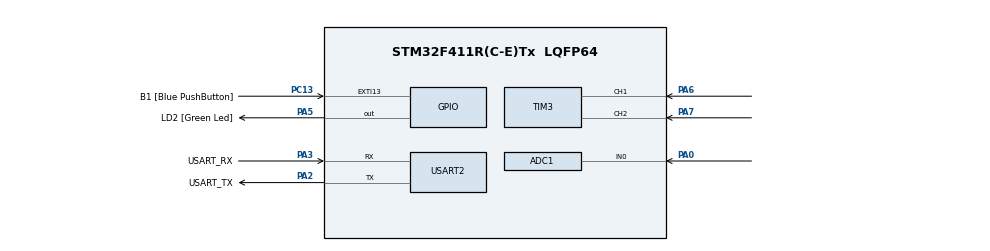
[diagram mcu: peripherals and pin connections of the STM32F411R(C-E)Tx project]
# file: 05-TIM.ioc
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Mcu.Family=STM32F4
RCC.CortexFreq_Value=100000000
Dma.TIM3_CH2.1.Mode=DMA_NORMAL
PA14.GPIO_Label=TCK
Dma.TIM3_CH1/TRIG.0.MemDataAlignment=DMA_MDATAALIGN_HALFWORD
Dma.TIM3_CH2.1.MemDataAlignment=DMA_MDATAALIGN_HALFWORD
NVIC.DMA1_Stream4_IRQn=true\:0\:0\:false\:false\:true\:false\:true
RCC.SYSCLKSource=RCC_SYSCLKSOURCE_PLLCLK
ProjectManager.StackSize=0x400
Dma.TIM3_CH2.1.PeriphInc=DMA_PINC_DISABLE
PH0\ -\ OSC_IN.Signal=RCC_OSC_IN
Dma.TIM3_CH2.1.Priority=DMA_PRIORITY_LOW
RCC.HCLKFreq_Value=100000000
RCC.APB2TimFreq_Value=100000000
Dma.TIM3_CH2.1.PeriphDataAlignment=DMA_PDATAALIGN_HALFWORD
RCC.AHBFreq_Value=100000000
ADC1.Channel-0\#ChannelRegularConversion=ADC_CHANNEL_0
RCC.HSE_VALUE=8000000
TIM3.Channel-Input_Capture1_from_TI1=TIM_CHANNEL_1
PC13-ANTI_TAMP.Signal=GPXTI13
PC14-OSC32_IN.Mode=LSE-External-Oscillator
Dma.TIM3_CH2.1.MemInc=DMA_MINC_ENABLE
Dma.TIM3_CH1/TRIG.0.PeriphDataAlignment=DMA_PDATAALIGN_HALFWORD
PA14.Mode=Serial_Wire
Dma.TIM3_CH1/TRIG.0.Priority=DMA_PRIORITY_LOW
SH.ADCx_IN0.0=ADC1_IN0,IN0
SH.S_TIM3_CH1.0=TIM3_CH1,Input_Capture1_from_TI1
ADC1.SamplingTime-0\#ChannelRegularConversion=ADC_SAMPLETIME_3CYCLES
RCC.FLatency-AdvancedSettings=FLASH_LATENCY_3
Mcu.Package=LQFP64
PA6.Signal=S_TIM3_CH1
USART2.VirtualMode=VM_ASYNC
PA2.GPIO_Label=USART_TX
Dma.TIM3_CH2.1.FIFOMode=DMA_FIFOMODE_DISABLE
Dma.TIM3_CH2.1.Instance=DMA1_Stream5
Dma.Request1=TIM3_CH2
RCC.APB1TimFreq_Value=100000000
Dma.Request0=TIM3_CH1/TRIG
VP_TIM3_VS_ClockSourceINT.Mode=Internal
PA3.Signal=USART2_RX
PB3.GPIO_Label=SWO
PC15-OSC32_OUT.Mode=LSE-External-Oscillator
ADC1.Rank-0\#ChannelRegularConversion=1
TIM3.Channel-Input_Capture2_from_TI2=TIM_CHANNEL_2
PC13-ANTI_TAMP.GPIO_Label=B1 [Blue PushButton]
Dma.TIM3_CH1/TRIG.0.PeriphInc=DMA_PINC_DISABLE
PH1\ -\ OSC_OUT.Mode=HSE-External-Clock-Source
Dma.TIM3_CH2.1.Direction=DMA_PERIPH_TO_MEMORY
Dma.TIM3_CH1/TRIG.0.MemInc=DMA_MINC_ENABLE
RCC.APB1CLKDivider=RCC_HCLK_DIV2
PC14-OSC32_IN.Signal=RCC_OSC32_IN
PA0-WKUP.Signal=ADCx_IN0
PA13.Signal=SYS_JTMS-SWDIO
PA3.Mode=Asynchronous
PH0\ -\ OSC_IN.Mode=HSE-External-Clock-Source
ProjectManager.TargetToolchain=STM32CubeIDE
NVIC.DMA1_Stream5_IRQn=true\:0\:0\:false\:false\:true\:false\:true
PC15-OSC32_OUT.Signal=RCC_OSC32_OUT
PA5.Signal=GPIO_Output
SH.S_TIM3_CH2.0=TIM3_CH2,Input_Capture2_from_TI2
PH1\ -\ OSC_OUT.Signal=RCC_OSC_OUT
board=NUCLEO-F411RE
RCC.VCOOutputFreq_Value=200000000
ADC1.EnableAnalogWatchDog=false
RCC.APB2Freq_Value=100000000
PA13.Mode=Serial_Wire
Mcu.Name=STM32F411R(C-E)Tx
Dma.TIM3_CH1/TRIG.0.FIFOMode=DMA_FIFOMODE_DISABLE
PA13.GPIO_Label=TMS
PA2.Signal=USART2_TX
Dma.TIM3_CH1/TRIG.0.Mode=DMA_NORMAL
RCC.48MHZClocksFreq_Value=50000000
PB3.Signal=SYS_JTDO-SWO
RCC.SYSCLKFreq_VALUE=100000000
ADC1.master=1
PA5.GPIO_Label=LD2 [Green Led]
Dma.TIM3_CH1/TRIG.0.Direction=DMA_PERIPH_TO_MEMORY
PC13-ANTI_TAMP.GPIO_ModeDefaultEXTI=GPIO_MODE_IT_FALLING
PA14.Signal=SYS_JTCK-SWCLK
ProjectManager.HeapSize=0x200
RCC.HSI_VALUE=16000000
NVIC.PriorityGroup=NVIC_PRIORITYGROUP_0
ADC1.NbrOfConversionFlag=1
Dma.TIM3_CH1/TRIG.0.Instance=DMA1_Stream4
RCC.PLLM=8
RCC.PLLN=100
PA2.Mode=Asynchronous
RCC.APB1Freq_Value=50000000
PA3.GPIO_Label=USART_RX
PA7.Signal=S_TIM3_CH2

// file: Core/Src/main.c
/* USER CODE BEGIN Header */
/**
  ******************************************************************************
  * @file           : main.c
  * @brief          : Main program body
  ******************************************************************************
  * @attention
  *
  * <h2><center>&copy; Copyright (c) 2021 STMicroelectronics.
  * All rights reserved.</center></h2>
  *
  * This software component is licensed by ST under BSD 3-Clause license,
  * the "License"; You may not use this file except in compliance with the
  * License. You may obtain a copy of the License at:
  *                        opensource.org/licenses/BSD-3-Clause
  *
  ******************************************************************************
  */
/* USER CODE END Header */
#include "main.h"

ADC_HandleTypeDef hadc1;

TIM_HandleTypeDef htim3;
DMA_HandleTypeDef hdma_tim3_ch1_trig;
DMA_HandleTypeDef hdma_tim3_ch2;

UART_HandleTypeDef huart2;

void SystemClock_Config(void);
static void MX_GPIO_Init(void);
static void MX_DMA_Init(void);
static void MX_USART2_UART_Init(void);
static void MX_TIM3_Init(void);
static void MX_ADC1_Init(void);

int main(void)
{

  /* MCU Configuration--------------------------------------------------------*/

  /* Reset of all peripherals, Initializes the Flash interface and the Systick. */
  HAL_Init();

  /* Configure the system clock */
  SystemClock_Config();

  /* Initialize all configured peripherals */
  MX_GPIO_Init();
  MX_DMA_Init();
  MX_USART2_UART_Init();
  MX_TIM3_Init();
  MX_ADC1_Init();

  /* Infinite loop */
  while (1)
  {

    /* USER CODE BEGIN 3 */
	  __HAL_DMA_GET_COUNTER(htim3->hdma);
  }
  /* USER CODE END 3 */
}

void SystemClock_Config(void)
{
  RCC_OscInitTypeDef RCC_OscInitStruct = {0};
  RCC_ClkInitTypeDef RCC_ClkInitStruct = {0};

  /** Configure the main internal regulator output voltage
  */
  __HAL_RCC_PWR_CLK_ENABLE();
  __HAL_PWR_VOLTAGESCALING_CONFIG(PWR_REGULATOR_VOLTAGE_SCALE1);
  /** Initializes the RCC Oscillators according to the specified parameters
  * in the RCC_OscInitTypeDef structure.
  */
  RCC_OscInitStruct.OscillatorType = RCC_OSCILLATORTYPE_HSI;
  RCC_OscInitStruct.HSIState = RCC_HSI_ON;
  RCC_OscInitStruct.HSICalibrationValue = RCC_HSICALIBRATION_DEFAULT;
  RCC_OscInitStruct.PLL.PLLState = RCC_PLL_ON;
  RCC_OscInitStruct.PLL.PLLSource = RCC_PLLSOURCE_HSI;
  RCC_OscInitStruct.PLL.PLLM = 16;
  RCC_OscInitStruct.PLL.PLLN = 336;
  RCC_OscInitStruct.PLL.PLLP = RCC_PLLP_DIV4;
  RCC_OscInitStruct.PLL.PLLQ = 4;
  if (HAL_RCC_OscConfig(&RCC_OscInitStruct) != HAL_OK)
  {
    Error_Handler();
  }
  /** Initializes the CPU, AHB and APB buses clocks
  */
  RCC_ClkInitStruct.ClockType = RCC_CLOCKTYPE_HCLK|RCC_CLOCKTYPE_SYSCLK
                              |RCC_CLOCKTYPE_PCLK1|RCC_CLOCKTYPE_PCLK2;
  RCC_ClkInitStruct.SYSCLKSource = RCC_SYSCLKSOURCE_PLLCLK;
  RCC_ClkInitStruct.AHBCLKDivider = RCC_SYSCLK_DIV1;
  RCC_ClkInitStruct.APB1CLKDivider = RCC_HCLK_DIV2;
  RCC_ClkInitStruct.APB2CLKDivider = RCC_HCLK_DIV1;

  if (HAL_RCC_ClockConfig(&RCC_ClkInitStruct, FLASH_LATENCY_2) != HAL_OK)
  {
    Error_Handler();
  }
}

static void MX_ADC1_Init(void)
{

  ADC_ChannelConfTypeDef sConfig = {0};

  /** Configure the global features of the ADC (Clock, Resolution, Data Alignment and number of conversion)
  */
  hadc1.Instance = ADC1;
  hadc1.Init.ClockPrescaler = ADC_CLOCK_SYNC_PCLK_DIV4;
  hadc1.Init.Resolution = ADC_RESOLUTION_12B;
  hadc1.Init.ScanConvMode = DISABLE;
  hadc1.Init.ContinuousConvMode = DISABLE;
  hadc1.Init.DiscontinuousConvMode = DISABLE;
  hadc1.Init.ExternalTrigConvEdge = ADC_EXTERNALTRIGCONVEDGE_NONE;
  hadc1.Init.ExternalTrigConv = ADC_SOFTWARE_START;
  hadc1.Init.DataAlign = ADC_DATAALIGN_RIGHT;
  hadc1.Init.NbrOfConversion = 1;
  hadc1.Init.DMAContinuousRequests = DISABLE;
  hadc1.Init.EOCSelection = ADC_EOC_SINGLE_CONV;
  if (HAL_ADC_Init(&hadc1) != HAL_OK)
  {
    Error_Handler();
  }
  /** Configure for the selected ADC regular channel its corresponding rank in the sequencer and its sample time.
  */
  sConfig.Channel = ADC_CHANNEL_0;
  sConfig.Rank = 1;
  sConfig.SamplingTime = ADC_SAMPLETIME_3CYCLES;
  if (HAL_ADC_ConfigChannel(&hadc1, &sConfig) != HAL_OK)
  {
    Error_Handler();
  }

}

static void MX_TIM3_Init(void)
{

  TIM_ClockConfigTypeDef sClockSourceConfig = {0};
  TIM_MasterConfigTypeDef sMasterConfig = {0};
  TIM_IC_InitTypeDef sConfigIC = {0};

  htim3.Instance = TIM3;
  htim3.Init.Prescaler = 0;
  htim3.Init.CounterMode = TIM_COUNTERMODE_UP;
  htim3.Init.Period = 65535;
  htim3.Init.ClockDivision = TIM_CLOCKDIVISION_DIV1;
  htim3.Init.AutoReloadPreload = TIM_AUTORELOAD_PRELOAD_DISABLE;
  if (HAL_TIM_Base_Init(&htim3) != HAL_OK)
  {
    Error_Handler();
  }
  sClockSourceConfig.ClockSource = TIM_CLOCKSOURCE_INTERNAL;
  if (HAL_TIM_ConfigClockSource(&htim3, &sClockSourceConfig) != HAL_OK)
  {
    Error_Handler();
  }
  if (HAL_TIM_IC_Init(&htim3) != HAL_OK)
  {
    Error_Handler();
  }
  sMasterConfig.MasterOutputTrigger = TIM_TRGO_RESET;
  sMasterConfig.MasterSlaveMode = TIM_MASTERSLAVEMODE_DISABLE;
  if (HAL_TIMEx_MasterConfigSynchronization(&htim3, &sMasterConfig) != HAL_OK)
  {
    Error_Handler();
  }
  sConfigIC.ICPolarity = TIM_INPUTCHANNELPOLARITY_RISING;
  sConfigIC.ICSelection = TIM_ICSELECTION_DIRECTTI;
  sConfigIC.ICPrescaler = TIM_ICPSC_DIV1;
  sConfigIC.ICFilter = 0;
  if (HAL_TIM_IC_ConfigChannel(&htim3, &sConfigIC, TIM_CHANNEL_1) != HAL_OK)
  {
    Error_Handler();
  }
  if (HAL_TIM_IC_ConfigChannel(&htim3, &sConfigIC, TIM_CHANNEL_2) != HAL_OK)
  {
    Error_Handler();
  }

}

static void MX_USART2_UART_Init(void)
{

  huart2.Instance = USART2;
  huart2.Init.BaudRate = 115200;
  huart2.Init.WordLength = UART_WORDLENGTH_8B;
  huart2.Init.StopBits = UART_STOPBITS_1;
  huart2.Init.Parity = UART_PARITY_NONE;
  huart2.Init.Mode = UART_MODE_TX_RX;
  huart2.Init.HwFlowCtl = UART_HWCONTROL_NONE;
  huart2.Init.OverSampling = UART_OVERSAMPLING_16;
  if (HAL_UART_Init(&huart2) != HAL_OK)
  {
    Error_Handler();
  }

}

static void MX_DMA_Init(void)
{

  /* DMA controller clock enable */
  __HAL_RCC_DMA1_CLK_ENABLE();

  /* DMA interrupt init */
  /* DMA1_Stream4_IRQn interrupt configuration */
  HAL_NVIC_SetPriority(DMA1_Stream4_IRQn, 0, 0);
  HAL_NVIC_EnableIRQ(DMA1_Stream4_IRQn);
  /* DMA1_Stream5_IRQn interrupt configuration */
  HAL_NVIC_SetPriority(DMA1_Stream5_IRQn, 0, 0);
  HAL_NVIC_EnableIRQ(DMA1_Stream5_IRQn);

}

static void MX_GPIO_Init(void)
{
  GPIO_InitTypeDef GPIO_InitStruct = {0};

  /* GPIO Ports Clock Enable */
  __HAL_RCC_GPIOC_CLK_ENABLE();
  __HAL_RCC_GPIOH_CLK_ENABLE();
  __HAL_RCC_GPIOA_CLK_ENABLE();
  __HAL_RCC_GPIOB_CLK_ENABLE();

  /*Configure GPIO pin Output Level */
  HAL_GPIO_WritePin(LD2_GPIO_Port, LD2_Pin, GPIO_PIN_RESET);

  /*Configure GPIO pin : B1_Pin */
  GPIO_InitStruct.Pin = B1_Pin;
  GPIO_InitStruct.Mode = GPIO_MODE_IT_FALLING;
  GPIO_InitStruct.Pull = GPIO_NOPULL;
  HAL_GPIO_Init(B1_GPIO_Port, &GPIO_InitStruct);

  /*Configure GPIO pin : LD2_Pin */
  GPIO_InitStruct.Pin = LD2_Pin;
  GPIO_InitStruct.Mode = GPIO_MODE_OUTPUT_PP;
  GPIO_InitStruct.Pull = GPIO_NOPULL;
  GPIO_InitStruct.Speed = GPIO_SPEED_FREQ_LOW;
  HAL_GPIO_Init(LD2_GPIO_Port, &GPIO_InitStruct);

}

void Error_Handler(void)
{
  __disable_irq();
  while (1)
  {
  }
}

/************************ (C) COPYRIGHT STMicroelectronics *****END OF FILE****/
